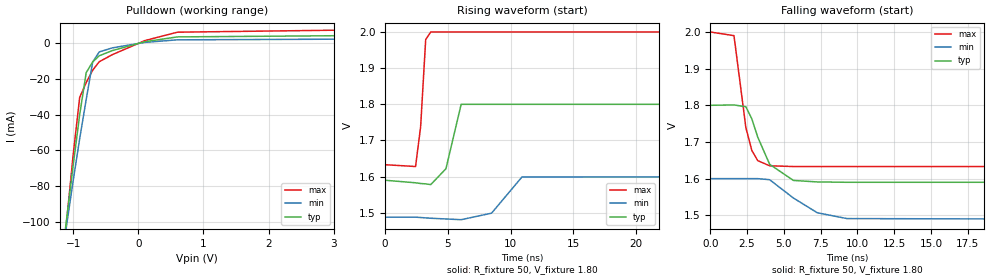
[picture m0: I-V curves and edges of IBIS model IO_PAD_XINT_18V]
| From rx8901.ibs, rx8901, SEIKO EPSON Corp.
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[Model]   IO_PAD_XINT_18V
Model_type Open_drain
Polarity Non-Inverting
Vref=2.00
Vmeas=0.90
Rref=5000
C_comp   2.5p   2.0p   3.0p
[Temperature Range] 25   105   -40
[Voltage Range]   1.80   1.60   2.00
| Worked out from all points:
|   slope of the pulldown table from 0 to 0.27 V, typ, clamps not added: 124 ohm
|   falling waveform, R_fixture 50, V_fixture 1.80: 20-80 % time 1.3ns typ, 2.23ns min, 822ps max; typ from 1.8 V to 1.59 V
|   rising waveform, R_fixture 50, V_fixture 1.80: 20-80 % time 655ps typ, 1.38ns min, 431ps max; typ from 1.59 V to 1.8 V
[Pulldown]
-1.8V     -323.1mA   -279.7mA   -381.9mA
-1.2V     -129.7mA   -126.9mA   -136.7mA
-1.1V     -98.33mA   -101.8mA   -99.52mA
-1V       -68.49mA   -77.09mA   -62.51mA
-900mV    -40mA      -53.48mA   -30.32mA
-800mV    -16.43mA   -31.46mA   -22mA
-700mV    -10.39mA   -10.43mA   -15.04mA
-600mV    -6.972mA   -4.818mA   -10.32mA
-400mV    -4.076mA   -2.558mA   -6.371mA
100mV     923.1uA    534.4uA    1.541mA
600mV     3.612mA    1.975mA    6.261mA
3.6V      4.437mA    2.42mA     7.642mA
[Falling Waveform]
R_fixture=50
V_fixture=1.80
V_fixture_min=1.60
V_fixture_max=2.00
0s        1.8V       1.6V       2V
1.616ns   1.801V     1.6V       1.99V
2.424ns   1.796V     1.6V       1.739V
2.828ns   1.763V     1.6V       1.677V
3.232ns   1.713V     1.6V       1.649V
4.04ns    1.639V     1.597V     1.635V
5.657ns   1.595V     1.547V     1.633V
7.273ns   1.591V     1.507V     1.633V
9.293ns   1.59V      1.491V     1.633V
40ns      1.59V      1.488V     1.633V
[Rising Waveform]
R_fixture=50
V_fixture=1.80
V_fixture_min=1.60
V_fixture_max=2.00
0s        1.59V      1.488V     1.633V
2.424ns   1.583V     1.488V     1.628V
2.828ns   1.581V     1.487V     1.738V
3.232ns   1.58V      1.486V     1.979V
3.636ns   1.578V     1.485V     2V
4.848ns   1.622V     1.483V     2V
6.061ns   1.8V       1.481V     2V
8.485ns   1.8V       1.499V     2V
10.91ns   1.8V       1.599V     2V
40ns      1.8V       1.6V       2V
[Ramp]
R_load=50
dV/dt_r   1.258E-1/6.209E-10   6.722E-2/1.379E-9   2.200E-1/3.830E-10
dV/dt_f   1.258E-1/1.281E-9   6.722E-2/2.203E-9   2.200E-1/7.525E-10
|[End   IO_PAD_XINT_18V
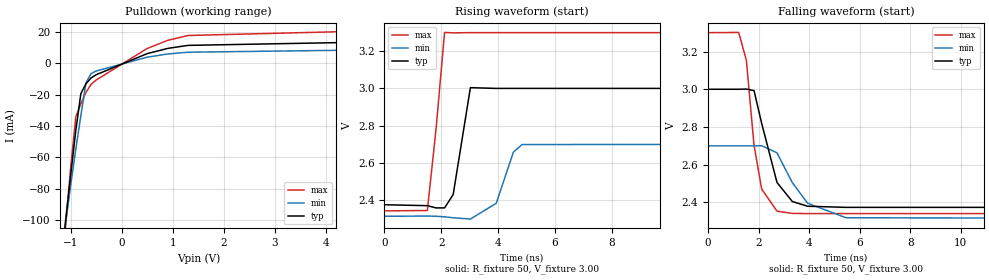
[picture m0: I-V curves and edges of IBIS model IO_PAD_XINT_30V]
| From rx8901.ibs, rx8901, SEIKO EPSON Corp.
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[Model]   IO_PAD_XINT_30V
Model_type Open_drain
Polarity Non-Inverting
Vref=3.30
Vmeas=1.50
Rref=5000
C_comp   2.5p   2.0p   3.0p
[Temperature Range] 25   105   -40
[Voltage Range]   3.00   2.70   3.30
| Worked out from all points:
|   slope of the pulldown table from 0 to 0.45 V, typ, clamps not added: 79 ohm
|   falling waveform, R_fixture 50, V_fixture 3.00: 20-80 % time 732ps typ, 1.12ns min, 495ps max; typ from 3 V to 2.37 V
|   rising waveform, R_fixture 50, V_fixture 3.00: 20-80 % time 399ps typ, 513ps min, 362ps max; typ from 2.37 V to 3 V
[Pulldown]
-3V       -719mA     -591.7mA   -886.7mA
-1.1V     -100.7mA   -102.4mA   -104mA
-1V       -71.53mA   -77.93mA   -66.69mA
-900mV    -42.98mA   -54.87mA   -34.29mA
-800mV    -19.25mA   -33.36mA   -25.77mA
-700mV    -13.01mA   -12.34mA   -18.5mA
-600mV    -9.326mA   -6.56mA    -13.4mA
-500mV    -7.242mA   -4.884mA   -10.62mA
500mV     6.223mA    3.955mA    9.514mA
900mV     9.547mA    6.005mA    14.7mA
1.3V      11.49mA    7.126mA    17.8mA
6V        14.3mA     9.054mA    21.64mA
[Falling Waveform]
R_fixture=50
V_fixture=3.00
V_fixture_min=2.70
V_fixture_max=3.30
0s        3V         2.7V       3.3V
1.212ns   3V         2.7V       3.301V
1.515ns   3.001V     2.7V       3.153V
1.818ns   2.993V     2.7V       2.704V
2.121ns   2.819V     2.701V     2.471V
2.727ns   2.506V     2.663V     2.354V
3.333ns   2.405V     2.505V     2.342V
3.939ns   2.38V      2.396V     2.341V
5.455ns   2.374V     2.319V     2.341V
30ns      2.374V     2.312V     2.341V
[Rising Waveform]
R_fixture=50
V_fixture=3.00
V_fixture_min=2.70
V_fixture_max=3.30
0s        2.374V     2.312V     2.341V
1.515ns   2.369V     2.313V     2.343V
1.818ns   2.357V     2.312V     2.776V
2.121ns   2.357V     2.309V     3.301V
2.424ns   2.429V     2.304V     3.299V
3.03ns    3.004V     2.297V     3.3V
3.939ns   3V         2.382V     3.3V
4.545ns   3V         2.658V     3.3V
4.848ns   3V         2.698V     3.3V
30ns      3V         2.7V       3.3V
[Ramp]
R_load=50
dV/dt_r   3.755E-1/3.227E-10   2.328E-1/4.880E-10   5.754E-1/2.199E-10
dV/dt_f   3.755E-1/7.066E-10   2.329E-1/1.095E-9   5.754E-1/4.704E-10
|[End   IO_PAD_XINT_30V
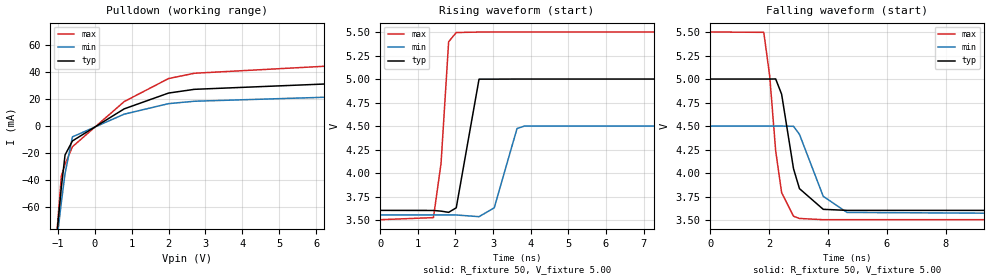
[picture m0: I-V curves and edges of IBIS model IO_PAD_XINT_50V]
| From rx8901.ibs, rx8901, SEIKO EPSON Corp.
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[Model]   IO_PAD_XINT_50V
Model_type Open_drain
Polarity Non-Inverting
Vref=5.50
Vmeas=2.50
Rref=5000
C_comp   2.5p   2.0p   3.0p
[Temperature Range] 25   105   -40
[Voltage Range]   5.00   4.50   5.50
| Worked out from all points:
|   slope of the pulldown table from 0 to 0.75 V, typ, clamps not added: 63 ohm
|   falling waveform, R_fixture 50, V_fixture 5.00: 20-80 % time 504ps typ, 719ps min, 384ps max; typ from 5 V to 3.6 V
|   rising waveform, R_fixture 50, V_fixture 5.00: 20-80 % time 292ps typ, 381ps min, 226ps max; typ from 3.6 V to 5 V
[Pulldown]
-5V       -1.392A    -1.127A    -1.738A
-1.1V     -103.5mA   -103.2mA   -107.3mA
-900mV    -45.54mA   -56.71mA   -37.26mA
-800mV    -21.64mA   -35.33mA   -28.5mA
-600mV    -11.21mA   -8.189mA   -15.49mA
800mV     12.6mA     8.658mA    18mA
2V        24.33mA    16.48mA    35.1mA
2.7V      27.11mA    18.26mA    39.04mA
7.3V      32.25mA    22.11mA    45.83mA
8.3V      39mA       26.99mA    55.11mA
9.5V      52.99mA    37.21mA    73.96mA
10V       60.61mA    42.84mA    84.12mA
[Falling Waveform]
R_fixture=50
V_fixture=5.00
V_fixture_min=4.50
V_fixture_max=5.50
0s        5V         4.5V       5.5V
1.818ns   5V         4.5V       5.496V
2.02ns    5V         4.5V       5.03V
2.222ns   5.001V     4.5V       4.238V
2.424ns   4.839V     4.5V       3.793V
2.828ns   4.048V     4.498V     3.543V
3.03ns    3.836V     4.413V     3.519V
3.838ns   3.616V     3.754V     3.506V
4.646ns   3.605V     3.583V     3.506V
20ns      3.605V     3.557V     3.506V
[Rising Waveform]
R_fixture=50
V_fixture=5.00
V_fixture_min=4.50
V_fixture_max=5.50
0s        3.605V     3.557V     3.506V
1.414ns   3.604V     3.557V     3.528V
1.616ns   3.597V     3.557V     4.104V
1.818ns   3.584V     3.557V     5.396V
2.02ns    3.632V     3.556V     5.494V
2.626ns   4.999V     3.538V     5.499V
3.03ns    4.999V     3.632V     5.5V
3.636ns   5V         4.474V     5.5V
3.838ns   5V         4.501V     5.5V
20ns      5V         4.5V       5.5V
[Ramp]
R_load=50
dV/dt_r   8.371E-1/2.509E-10   5.659E-1/3.444E-10   1.197E+0/1.922E-10
dV/dt_f   8.371E-1/4.893E-10   5.659E-1/7.092E-10   1.197E+0/3.549E-10
|[End   IO_PAD_XINT_50V
